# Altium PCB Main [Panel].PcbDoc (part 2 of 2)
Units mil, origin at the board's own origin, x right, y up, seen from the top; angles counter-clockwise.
Board outline 6300 x 4291.34 mil, 4 copper layers (Top Layer, MidLayer1, MidLayer2, Bottom Layer), stack 62.529 mil thick; 0 components, 266 nets, 12 pads, 0 vias.

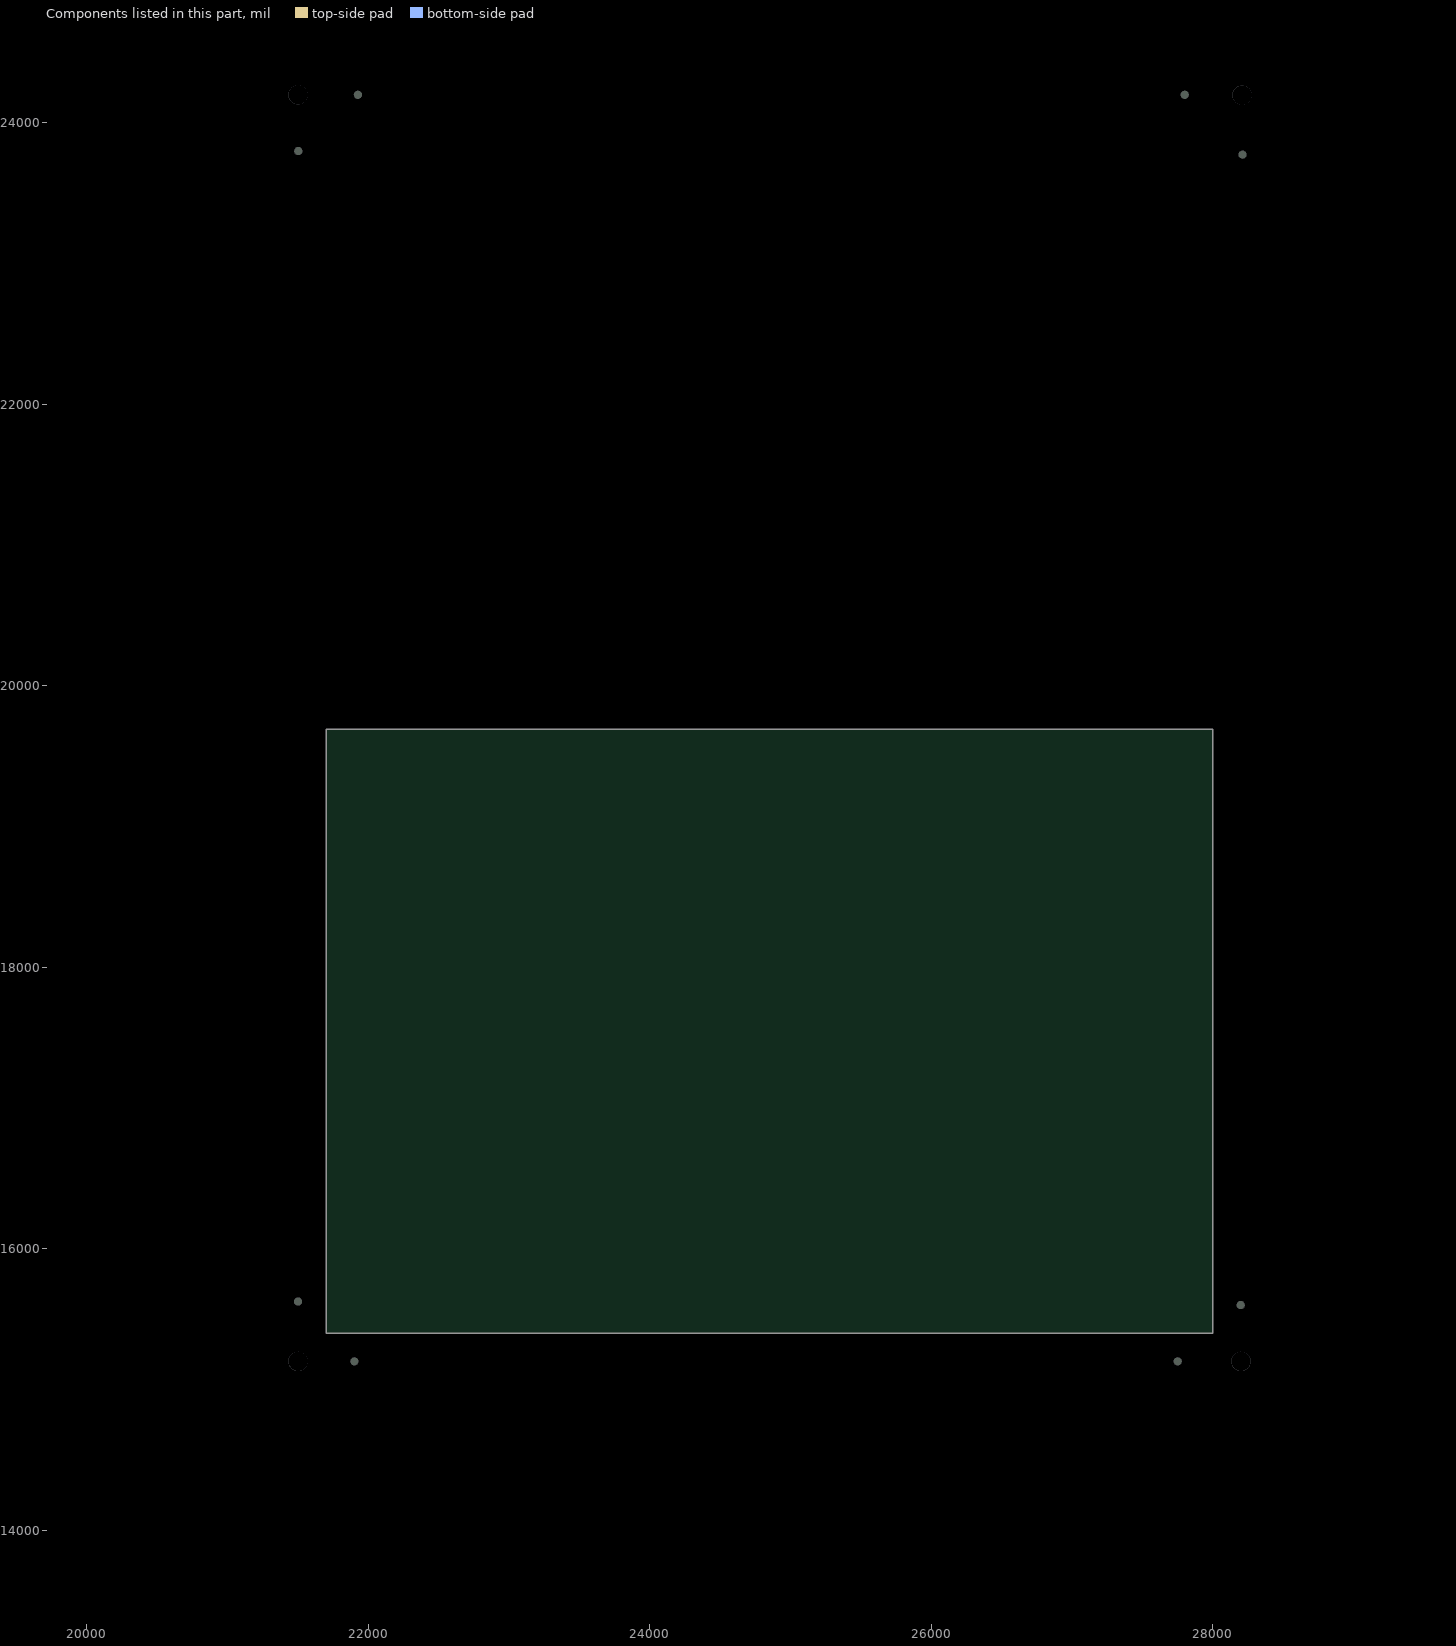
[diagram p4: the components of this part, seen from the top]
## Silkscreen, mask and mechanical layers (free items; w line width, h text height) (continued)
Bottom Solder:
  circle w7.87: c20777.95,24400 r59.06
  circle w7.87: c20777.95,24400 r19.69
  circle w7.87: c20777.95,24400 r98.43
  circle w7.87: c20788.98,15000 r59.06
  circle w7.87: c20788.98,15000 r19.69
  circle w7.87: c20788.98,15000 r98.43
  circle w7.87: c29000,24400 r98.43
  circle w7.87: c29000,24400 r19.69
  circle w7.87: c29000,24400 r59.06
  rectangle: 24567.76,24140.67 24961.46,24268.62
  rectangle: 24578.15,15140.67 24971.85,15268.62
  lines w7.87: 19893.7,13715.75 22137.79,13715.75 ; 20385.83,13518.9 20385.83,13715.75 ; 20659.84,24400 20777.95,24400 ; 20670.87,15000 20788.98,15000 ; 20777.95,24281.89 20777.95,24400 ; 20777.95,24518.11 20777.95,24400 ; 20788.98,14881.89 20788.98,15000 ; 20788.98,15118.11 20788.98,15000 ; 20896.06,24400 20777.95,24400 ; 20907.09,15000 20788.98,15000 ; 21803.15,13518.9 21803.15,13715.75 ; 22137.79,13518.9 22137.79,13715.75 ; 22137.79,13912.6 25917.32,13912.6 29500,13912.6 ; 22137.79,14109.45 25917.32,14109.45 ; 22137.79,14306.3 25917.32,14306.3 ; 22137.79,14503.15 25917.32,14503.15 ; 22767.72,13518.9 22767.72,14700 ; 23397.64,14700 23397.64,13518.9 23397.64,13715.75 ; 24027.56,13518.9 24027.56,14700 ; 24657.48,13518.9 24657.48,14700 ; 25287.4,13518.9 25287.4,14700 ; 26625.98,13518.9 26625.98,13912.6 ; 28122.05,13518.9 28122.05,13912.6 ; 28633.86,13518.9 28633.86,13912.6 ; 28881.89,24400 29000,24400 ; 29000,24281.89 29000,24400 ; 29000,24518.11 29000,24400 ; 29118.11,24400 29000,24400 ; 29500,13715.75 25917.32,13715.75 25287.4,13715.75 24657.48,13715.75 24027.56,13715.75 23397.64,13715.75 ; 22137.79,13715.75 22767.72,13715.75 23397.64,13715.75 ; 22137.79,13715.75 22137.79,14700 ; 22137.79,14700 25917.32,14700 ; 22137.79,14700 21507.87,14700 19893.7,14700 19893.7,13518.9 25917.32,13518.9 ; 25917.32,13518.9 29500,13518.9 29500,14700 25917.32,14700 ; 25917.32,13518.9 25917.32,14700
  text "TITLE" at 25996.06,14581.89 h98.43
  text "AGRIGEL" at 20061.16,14328.98 h393.7
  text ".PCB_TITLE" at 26114.17,14266.93 h196.85
  text "BOTTOM SIDE SOLDER MASK" at 26114.17,14109.45 h98.43
  text ".PCB_Drawn" at 22295.28,13794.49 h98.43
  text ".PCB_Checked" at 22885.83,13794.49 h98.43
  text ".PCB_Approved" at 23515.75,13794.49 h98.43
  text ".PRINT_DATE" at 24145.67,13794.49 h98.43
  text ".PCB_DocRevision" at 24696.85,13794.49 h98.43
  text ".PCB_ECRNo" at 25444.88,13794.49 h98.43
  text "DWG NUMBER" at 25956.69,13794.49 h98.43
  text ".PCB_Drawing Number" at 26704.72,13794.49 h98.43
  text "PCB VER" at 28161.42,13794.49 h98.43
  text "SHEET NO." at 28712.6,13794.49 h98.43
  text "PLOTFILE" at 19933.07,13597.64 h98.43
  text ".PCB_Plot File" at 20425.2,13597.64 h98.43
  text "GBS" at 21842.52,13597.64 h98.43
  text "DRAWN" at 22295.28,13597.64 h98.43
  text "CHECKED" at 22885.83,13597.64 h98.43
  text "APPROVED" at 23476.38,13597.64 h98.43
  text "DATE" at 24224.41,13597.64 h98.43
  text "DOC REV." at 24775.59,13597.64 h98.43
  text "ECR NO." at 25444.88,13597.64 h98.43
  text "SOURCE" at 25956.69,13597.64 h98.43
  text ".Pcb_File_Name_No_Path" at 26704.72,13597.64 h98.43
  text ".Version" at 28240.16,13597.64 h98.43
  text "SHEET" at 28712.6,13597.64 h98.43
  text "8" at 29066.93,13597.64 h98.43
  text "OF" at 29185.04,13597.64 h98.43
  text "9" at 29381.89,13597.64 h98.43
Board:
  lines w1: 21300,15200 21300,24200 ; 21500,15000 28200,15000 ; 21500,24400 28200,24400 ; 28400,15200 28400,24200
  lines w2: 21300,15200 ccw(c21500,15200) 21500,15000 ; 21300,24200 cw(c21500.97,24199.03) 21501.93,24400 ; 28200,15000 ccw(c28200,15200) 28400,15200 ; 28200,24400 cw(c28200,24200) 28400,24200
Drill Drawing:
  circle w4.92: c28299.29,12570.08 r39.37
  circle w4.92: c28299.29,12570.08 r118.11
  region: 21302.36,14997.13 21223.62,14957.76 21262.99,14918.39
  lines w1: 21300.34,15400 28000,15400 ; 21300.34,19691.34 28000,19691.34 28500,19691.34 ; 21300.34,23982.68 28000,23982.68 28500,23982.68 28800,23982.68 ; 21700,15000 21700,15400 21700,24800 ; 28000,15000 28000,15400 ; 28000,24800 28000,15400 ; 28400,23982.68 28400.66,23983.34 ; 28500.66,15400.66 28500,15400 ; 28500.66,19692 28500,19691.34 ; 28800,15400 28500,15400 ; 28800,19691.34 28500,19691.34 ; 28000,15400 28500,15400
  lines w7.87: 20633.07,14721.54 21026.77,14721.54 21302.36,14997.13 ; 25716.24,12570.08 28117.81,12570.08 ; 25716.61,12388.98 25716.61,13570.08 28118.19,13570.08 ; 25717,12766.93 28141.81,12766.93 28749,12766.06 32551.26,12766.93 ; 26464.27,12373.23 26464.27,12570.08 ; 27291.04,12373.23 27291.04,12570.08 ; 28118.19,12568.06 28118.19,13570.08 ; 28118.19,13176.38 28748.11,13176.38 32527.64,13176.38 ; 28161.5,12570.08 28712.68,12570.08 ; 28299.29,12432.29 28299.29,12707.88 ; 28748.11,12569.06 28748.11,13570.08 ; 28748.11,12979.53 32527.64,12979.53 ; 28748.11,13373.23 32527.64,13373.23 ; 29378.03,12388.98 29378.03,13570.08 ; 30007,12570.08 30661.5,12570.08 31291.42,12570.08 31921.34,12570.08 32528,12570.08 ; 30007.57,12373.23 30007.57,12570.08 29377.65,12570.08 28747.73,12570.08 ; 30007.95,12388.98 30007.95,13570.08 ; 30637.87,12388.98 30637.87,13570.08 ; 31267.8,12388.98 31267.8,13570.08 ; 31897.72,12388.98 31897.72,13570.08 ; 32527.26,12373.23 36857.97,12373.23 36857.97,12766.93 32527.26,12766.93 ; 32527.26,12570.08 36857.97,12570.08 ; 32527.64,12374.06 32527.64,13570.08 ; 32527.64,15341.73 36858.35,15341.73 ; 32527.64,16096.85 36858.35,16096.85 ; 32527.64,16293.7 36858.35,16293.7 ; 32528.11,16896.63 36858.82,16896.63 ; 32528.11,17093.48 36858.82,17093.48 ; 32528.11,17480.88 36858.82,17480.88 ; 32528.11,17679.31 32528.47,17677.94 32528.47,16701.99 ; 32528.11,17874.58 36858.82,17874.58 ; 32528.11,18071.43 36858.82,18071.43 36858.82,16701.99 ; 32528.11,18268.28 36858.82,18268.28 ; 32528.11,18465.13 36858.82,18465.13 ; 32528.11,18661.98 36858.82,18661.98 ; 32528.47,16700 36858.35,16700 36858.35,16896.87 ; 32528.47,16700.85 32528.47,16863.85 32528.47,16864.85 ; 32528.47,17670.49 32528.47,18465.35 32528.11,18466.71 32528.11,18858.83 36858.82,18858.83 36858.82,17670.49 ; 32842.6,15906.13 32842.6,16293.7 ; 32843.07,16701.99 32843.07,18664.58 ; 32881.97,14948.03 32881.97,15538.58 ; 33235.92,12373.23 33235.92,12766.93 ; 33472.52,13766.93 33472.52,14554.33 ; 34378.03,15906.13 34378.03,16293.7 ; 34378.5,16701.99 34378.5,17874.58 ; 34378.5,17670.49 34378.5,18661.98 ; 34496.14,15538.58 34574.88,15538.58 34574.88,14948.03 ; 35401.28,12373.23 35401.28,12766.93 ; 35913.09,12373.23 35913.09,12766.93 ; 35992.2,15900.22 35992.2,16293.7 ; 35992.68,16701.99 35992.68,17874.58 ; 35992.68,17670.49 35992.68,18661.98 ; 36385.9,15904.16 36385.9,16293.7 ; 36386.38,16701.99 36386.38,17874.58 ; 36386.38,17670.49 36386.38,18661.98 ; 36858,12373.23 18400,12373.23 18400,26599.06 36858.35,26599.06 36858.35,12388.98 ; 36858.35,13570.08 32527.64,13570.08 ; 36858.35,14357.48 32527.64,14357.48 ; 36858.35,14948.03 32527.64,14948.03 32527.64,15144.88 ; 36858.35,15144.88 32527.64,15144.88 ; 36858.35,15538.58 32527.64,15538.58 ; 36858.35,15735.43 32527.64,15735.43 32527.64,15538.58 ; 36858.35,15900 32530.67,15900 32527.64,15903.03 32527.64,16490.55 36858.35,16490.55 36858.35,15900.22 ; 28117.81,12570.08 28117.81,12373.23 28117.81,12570.08 ; 28118.19,13570.08 28748.11,13570.08 ; 28747.73,12373.23 28747.73,12570.08 ; 28747.73,12373.23 28747.73,12570.08 ; 28747.73,12373.23 28747.73,12570.08 ; 28748.11,13570.08 32527.64,13570.08 ; 32527.64,13766.93 36858.35,13766.93 32527.64,13766.93 ; 32527.64,13766.93 32527.64,13963.78 ; 32527.64,13766.93 32527.64,14751.18 ; 32527.64,13963.78 36858.35,13963.78 36858.35,14160.63 32527.64,14160.63 32527.64,13963.78 ; 32527.64,13963.78 32527.64,14357.48 ; 32527.64,14357.48 32527.64,14554.33 ; 32527.64,14554.33 36858.35,14554.33 32527.64,14554.33 ; 32527.64,14554.33 32527.64,14751.18 ; 32527.64,14751.18 36858.35,14751.18 32527.64,14751.18 ; 32527.64,15144.88 32527.64,15538.58 ; 28456.77,12530.71 28692.99,12451.97 28692.99,12688.19 28456.77,12609.45 28456.77,12570.08 28456.77,12530.71 ; 32528.11,17284.03 36858.82,17284.03 32528.11,17284.03 ; 32528.11,17677.73 36858.82,17677.73 32528.11,17677.73
  text "V-SCORE" at 21485,24845 h100
  text "V-SCORE" at 27785,24845 h100
  text "V-SCORE" at 28878.66,24197.68 h100 r270
  text "V-SCORE" at 28878.66,19906.34 h100 r270
  text ".Legend" at 31800,19100 h78.74
  text "LAYER BUILD DATA" at 33787.95,18740.72 h118.11
  text "SHT" at 32606.85,18543.87 h98.43
  text "DESCRIPTION" at 32921.81,18543.87 h98.43
  text "PLOTFILE" at 34457.24,18543.87 h98.43
  text "EXT" at 36110.79,18543.87 h98.43
  text "P/N" at 36543.86,18543.87 h98.43
  text "GD1" at 36076.42,18353.05 h98.43
  text "1" at 32685.59,18347.02 h98.43
  text "CUTTING & DRILLING DRAWING" at 32921.81,18347.02 h98.43
  text ".PCB_Plot File" at 34457.24,18347.02 h98.43
  text "-" at 36543.86,18347.02 h98.43
  text "GTO" at 36076.42,18156.2 h98.43
  text "2" at 32685.59,18150.17 h98.43
  text "TOP SIDE LEGEND" at 32921.81,18150.17 h98.43
  text ".PCB_Plot File" at 34457.24,18150.17 h98.43
  text "POS" at 36543.86,18150.17 h98.43
  text "GTS" at 36076.42,17959.35 h98.43
  text "3" at 32685.59,17953.32 h98.43
  text "TOP SIDE SOLDER MASK" at 32921.81,17953.32 h98.43
  text ".PCB_Plot File" at 34457.24,17953.32 h98.43
  text "NEG" at 36543.86,17953.32 h98.43
  text "GTL" at 36076.42,17762.5 h98.43
  text "4" at 32685.59,17756.47 h98.43
  text "TOP SIDE" at 32921.81,17756.47 h98.43
  text ".PCB_Plot File" at 34457.24,17756.47 h98.43
  text "POS" at 36543.86,17756.47 h98.43
  text "G1" at 36076.42,17565.65 h98.43
  text "5" at 32685.59,17559.62 h98.43
  text "INTERNAL LAYER 1" at 32921.81,17559.62 h98.43
  text ".PCB_Plot File" at 34457.24,17559.62 h98.43
  text "POS" at 36543.86,17559.62 h98.43
  text "G2" at 36076.42,17368.8 h98.43
  text "6" at 32685.59,17362.77 h98.43
  text "INTERNAL LAYER 2" at 32921.81,17362.77 h98.43
  text ".PCB_Plot File" at 34457.24,17362.77 h98.43
  text "POS" at 36543.86,17362.77 h98.43
  text "GBL" at 36076.42,17178.25 h98.43
  text "BOTTOM SIDE" at 32921.81,17172.22 h98.43
  text ".PCB_Plot File" at 34457.24,17172.22 h98.43
  text "POS" at 36543.86,17172.22 h98.43
  text "7" at 32685.59,17165.92 h98.43
  text "GBS" at 36076.42,16981.4 h98.43
  text "BOTTOM SIDE SOLDER MASK" at 32921.81,16975.37 h98.43
  text ".PCB_Plot File" at 34457.24,16975.37 h98.43
  text "NEG" at 36543.86,16975.37 h98.43
  text "8" at 32685.59,16969.07 h98.43
  text "GBO" at 36076.78,16784.77 h98.43
  text "9" at 32685.95,16778.74 h98.43
  text "BOTTOM SIDE LEGEND" at 32922.17,16778.74 h98.43
  text ".PCB_Plot File" at 34457.61,16778.74 h98.43
  text "POS" at 36544.22,16778.74 h98.43
  text "SOLDER STENCIL DATA" at 33787.48,16372.44 h118.11
  text "SHT" at 32606.38,16175.59 h98.43
  text "DESCRIPTION" at 32921.34,16175.59 h98.43
  text "PLOTFILE" at 34456.77,16175.59 h98.43
  text "EXT" at 36110.31,16175.59 h98.43
  text "P/N" at 36543.38,16175.59 h98.43
  text "GTP" at 36075.94,15984.77 h98.43
  text "1" at 32685.12,15978.74 h98.43
  text "TOP SIDE SOLDER STENCIL" at 32921.34,15978.74 h98.43
  text ".PCB_Plot File" at 34456.77,15978.74 h98.43
  text "POS" at 36543.38,15978.74 h98.43
  text "MATERIAL" at 34220.55,15617.32 h118.11
  text "V-SCORE" at 28878.66,15615 h100 r270
  text "ITEM" at 32606.38,15420.47 h98.43
  text "FINAL THICKNESS" at 33236.3,15420.47 h98.43
  text "MATERIAL" at 35126.06,15420.47 h98.43
  text "Cu" at 32606.38,15223.62 h98.43
  text "35um (ON ALL LAYERS)" at 33236.3,15223.62 h98.43
  text "COPPER CLAD" at 35126.06,15223.62 h98.43
  text "PCB" at 32606.38,15026.77 h98.43
  text "1.60mm" at 33236.3,15026.77 h98.43
  text "NEMA FR4" at 35126.06,15026.77 h98.43
  text "NC DRILL" at 20633.07,14642.8 h78.74
  text "FINISH" at 34181.18,14633.07 h118.11
  text "ORIGIN" at 20633.07,14564.06 h78.74
  text "X = 0 ; Y = 0" at 20633.07,14485.32 h78.74
  text "ITEM" at 32645.75,14436.22 h98.43
  text "DESCRIPTION" at 33590.63,14436.22 h98.43
  text "PCB" at 32645.75,14239.37 h98.43
  text "IMMERSION GOLD" at 33590.63,14239.37 h98.43
  text "SOLDER MASK" at 32645.75,14042.52 h98.43
  text "GREEN PHOTO-IMAGEABLE" at 33590.63,14042.52 h98.43
  text "LEGEND" at 32645.75,13845.67 h98.43
  text "WHITE EPOXY" at 33590.63,13845.67 h98.43
  text "TITLE" at 32606.38,13451.97 h98.43
  text "UNITS" at 28315.04,13412.6 h98.43
  text "METRIC" at 28275.67,13294.49 h98.43
  text "AGRIGEL" at 25884.08,13199.06 h393.7
  text ".PCB_TITLE" at 32842.6,13176.38 h196.85
  text "(CUTTING & DRILLING DRAWING)" at 32881.97,13058.27 h98.43
  text "SCALE" at 28275.67,13018.9 h98.43
  text "N/A" at 28354.41,12900.79 h98.43
  text "TOLERANCES UNLESS OTHERWISE STATED" at 25992.2,12664.57 h98.43
  text ".PCB_Drawn" at 28905.59,12664.57 h98.43
  text ".PCB_Checked" at 29496.14,12664.57 h98.43
  text ".PCB_Approved" at 30126.06,12664.57 h98.43
  text ".PRINT_DATE" at 30755.98,12664.57 h98.43
  text ".PCB_DocRevision" at 31307.17,12664.57 h98.43
  text ".PCB_ECRNo" at 32055.2,12664.57 h98.43
  text "DWG NUMBER" at 32543.01,12664.57 h98.43
  text ".PCB_Drawing Number" at 33291.04,12664.57 h98.43
  text "PCB VER" at 35417.02,12664.57 h98.43
  text "SHEET NO." at 36204.43,12664.57 h98.43
  text "1 = +/-0.2" at 25889.46,12467.72 h98.43
  text "1.0 = +/-0.1" at 26637.5,12467.72 h98.43
  text "1.00 = +/-0.5" at 27424.9,12467.72 h98.43
  text "DRAWN" at 28881.59,12467.72 h98.43
  text "CHECKED" at 29472.14,12467.72 h98.43
  text "APPROVED" at 30086.69,12467.72 h98.43
  text "DATE" at 30834.72,12467.72 h98.43
  text "DOC REV." at 31385.91,12467.72 h98.43
  text "ECR NO." at 32055.2,12467.72 h98.43
  text "SOURCE" at 32543.01,12467.72 h98.43
  text ".Pcb_File_Name_No_Path" at 33291.04,12467.72 h98.43
  text ".Version" at 35495.76,12467.72 h98.43
  text "SHEET" at 35968.2,12467.72 h98.43
  text "1" at 36322.54,12467.72 h98.43
  text "OF" at 36440.65,12467.72 h98.43
  text "9" at 36637.5,12467.72 h98.43

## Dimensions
21300,15000 to 28500.66,15000 on Drill Drawing
21300,24400 to 21300,15000 on Drill Drawing

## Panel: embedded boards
"Main.PcbDoc" at 21700,15400, 2 rows x 1 columns, spacing 4291.34 x 1500, rotation 0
